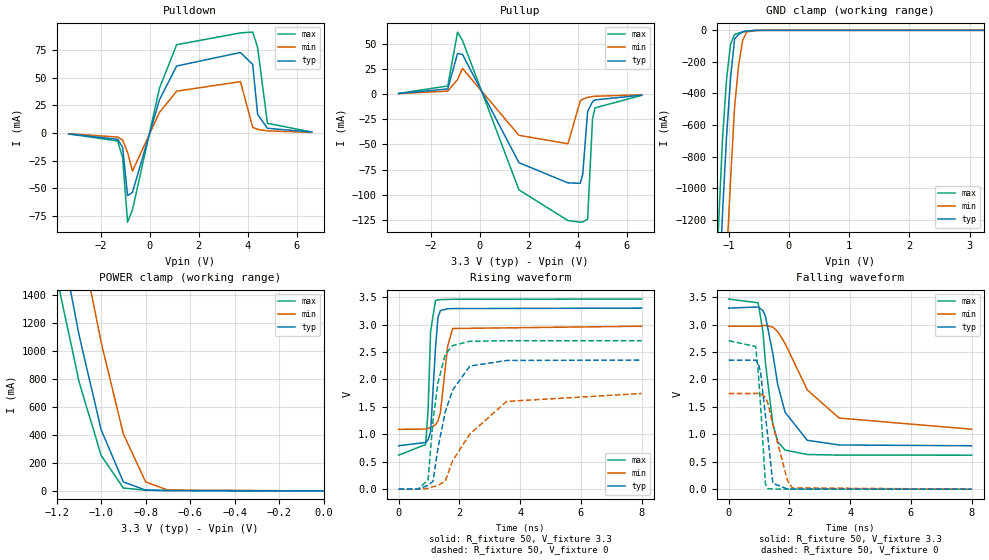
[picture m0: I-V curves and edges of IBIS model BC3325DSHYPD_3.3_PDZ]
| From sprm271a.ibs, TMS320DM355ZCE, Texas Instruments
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|   Model Cell BC3325DSHYPD_3.3_PDZ
[Model]   BC3325DSHYPD_3.3_PDZ
Model_type   I/O
Polarity   Non-Inverting
Enable   Active-Low
Vinl =  1.5
Vinh =  1.8
Cref =  15.0000pF
Rref =  100.0000M
Vref =  0V
Vmeas =  1.65
C_comp   0.972592p   0.9599789p   0.9808023p
[Model Spec]
Vinl   1.5   1.335   1.5825
Vinh   1.8   1.635   1.8825
[Temperature Range]   25   125   -40
[Voltage Range]   3.3   2.97   3.465
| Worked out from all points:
|   slope of the pulldown table from 0 to 0.495 V, typ, clamps not added: 13.9 ohm
|   slope of the pullup table from 0 to 0.495 V, typ, clamps not added: 18.5 ohm
|   GND clamp passes 1 mA (typ) near -0.58 V on its own axis
|   POWER clamp passes 1 mA (typ) near -0.55 V on its own axis
|   rising waveform, R_fixture 50, V_fixture 3.3: 20-80 % time 158ps typ, 222ps min, 118ps max; typ from 0.791 V to 3.3 V
|   rising waveform, R_fixture 50, V_fixture 0: 20-80 % time 596ps typ, 1.31ns min, 352ps max; typ from 0 V to 2.35 V
|   falling waveform, R_fixture 50, V_fixture 3.3: 20-80 % time 565ps typ, 1.23ns min, 332ps max; typ from 3.3 V to 0.791 V
|   falling waveform, R_fixture 50, V_fixture 0: 20-80 % time 265ps typ, 467ps min, 185ps max; typ from 2.35 V to 0 V
[POWER_clamp]
|   voltage   I(typ)   I(min)   I(max)
-3.3V     22.26A     22.98A     21.87A
-1.2V     1.951A     2.729A     1.539A
-1.167V   1.675A     2.441A     1.289A
-1.133V   1.4A       2.153A     1.039A
-1.1V     1.125A     1.865A     788.5mA
-1.067V   896.1mA    1.599A     610.5mA
-1.033V   667.5mA    1.332A     432.6mA
-1V       438.8mA    1.066A     254.7mA
-900mV    64.45mA    408.3mA    20.71mA
-800mV    5.784mA    64.77mA    5.201mA
-700mV    2.596mA    5.81mA     3.131mA
-11.55fV  459.8pA    9.235nA    231.7pA
[Pulldown]
|   voltage   I(typ)   I(min)   I(max)
-3.3V     -808.1uA   -658.5uA   -838.6uA
-1.3V     -5.711mA   -3.626mA   -7.219mA
-1.1V     -12.9mA    -6.318mA   -22.43mA
-900mV    -56.46mA   -17.38mA   -80.42mA
-700mV    -53.51mA   -34.37mA   -69.3mA
400mV     30.01mA    18.55mA    40.42mA
1.1V      60.43mA    37.7mA     79.59mA
3.7V      72.61mA    46.35mA    90.3mA
4.2V      61.81mA    5.119mA    91.01mA
4.4V      16.79mA    3.291mA    77.1mA
4.8V      4.263mA    1.885mA    8.734mA
6.6V      871.4uA    628.5uA    963.3uA
[Pullup]
|   voltage   I(typ)   I(min)   I(max)
-3.3V     659.6uA    522.1uA    739.6uA
-1.3V     5.125mA    2.966mA    8.081mA
-900mV    40.49mA    14.5mA     61.66mA
-700mV    39.49mA    25.52mA    53.37mA
1.6V      -68.17mA   -40.92mA   -95.13mA
3.6V      -88.21mA   -49.34mA   -125.7mA
4.1V      -88.68mA   -6.718mA   -127.3mA
4.2V      -79.89mA   -4.993mA   -127mA
4.4V      -17.25mA   -3.255mA   -124.4mA
4.6V      -7.503mA   -2.398mA   -24.77mA
4.7V      -5.775mA   -2.116mA   -13.67mA
6.6V      -1.03mA    -644.3uA   -1.277mA
[GND_clamp]
|   voltage   I(typ)   I(min)   I(max)
-3.3V     -22.38A    -23.15A    -21.96A
-1.167V   -1.724A    -2.574A    -1.236A
-1.1V     -1.154A    -1.991A    -682.8mA
-1.033V   -667.2mA   -1.446A    -306.2mA
-966.7mV  -300.6mA   -943.8mA   -87.41mA
-900mV    -54.63mA   -483.6mA   -26.4mA
-833.3mV  -26.33mA   -221.3mA   -17.61mA
-766.7mV  -9.637mA   -63.67mA   -10.28mA
-700mV    -4.559mA   -10.62mA   -4.393mA
-566.7mV  -684.4uA   -1.479mA   -425uA
-433.3mV  -37.24uA   -148.7uA   -12.97uA
3.233V    -358.1pA   12.24uA    151.9pA
[Ramp]
| variable   typ   min   max
dV/dt_f   1.518986/0.5662057n   1.136875/1.234065n   1.72203/0.3324217n
dV/dt_r   1.411442/0.5978231n   1.046603/1.31172n   1.623751/0.3450001n
R_load = 50
[Rising Waveform]
R_fixture = 50
V_fixture = 3.3
V_fixture_min = 2.97
V_fixture_max = 3.465
| time   V(typ)   V(min)   V(max)
|   time   V(typ)   V(min)   V(max)
0s        790.9mV    1.09V      619.8mV
888.9ps   850.5mV    1.095V     812.7mV
969.7ps   902.2mV    1.106V     1.458V
1.051ns   1.04V      1.124V     2.875V
1.212ns   2.567V     1.174V     3.438V
1.293ns   3.132V     1.242V     3.45V
1.374ns   3.256V     1.397V     3.454V
1.616ns   3.288V     2.613V     3.459V
1.778ns   3.292V     2.928V     3.461V
8ns       3.3V       2.97V      3.465V
[Rising Waveform]
R_fixture = 50
V_fixture = 0
V_fixture_min = 0
V_fixture_max = 0
| time   V(typ)   V(min)   V(max)
|   time   V(typ)   V(min)   V(max)
0s        34.16nV    295.6nV    3.065nV
646.5ps   -563.6uV   -213.6uV   2.59mV
969.7ps   70.49mV    13.11mV    168.8mV
1.131ns   142.8mV    43.34mV    1.262V
1.293ns   746.6mV    65.7mV     1.937V
1.535ns   1.413V     149.8mV    2.456V
1.778ns   1.805V     519.9mV    2.617V
2.343ns   2.244V     1.003V     2.695V
3.556ns   2.346V     1.599V     2.706V
8ns       2.352V     1.744V     2.706V
[Falling Waveform]
R_fixture = 50
V_fixture = 3.3
V_fixture_min = 2.97
V_fixture_max = 3.465
| time   V(typ)   V(min)   V(max)
|   time   V(typ)   V(min)   V(max)
0s        3.3V       2.97V      3.465V
969.7ps   3.321V     2.97V      3.397V
1.131ns   3.252V     2.98V      2.856V
1.212ns   3.149V     2.986V     2.294V
1.455ns   2.467V     2.954V     1.187V
1.616ns   1.904V     2.872V     863.2mV
1.859ns   1.401V     2.655V     712.6mV
2.586ns   890.9mV    1.811V     631.8mV
3.636ns   805.7mV    1.296V     620.6mV
8ns       790.9mV    1.093V     619.8mV
[Falling Waveform]
R_fixture = 50
V_fixture = 0
V_fixture_min = 0
V_fixture_max = 0
| time   V(typ)   V(min)   V(max)
|   time   V(typ)   V(min)   V(max)
0s        2.352V     1.744V     2.706V
888.9ps   2.35V      1.744V     2.6V
969.7ps   2.297V     1.747V     2.161V
1.051ns   2.13V      1.745V     1.526V
1.212ns   1.332V     1.668V     91.88mV
1.293ns   934.1mV    1.567V     9.454mV
1.455ns   107.7mV    1.176V     3.012mV
1.939ns   2.2mV      151.1mV    864.6uV
2.101ns   1.638mV    23.13mV    585.3uV
8ns       326.2nV    9.667uV    152.3nV
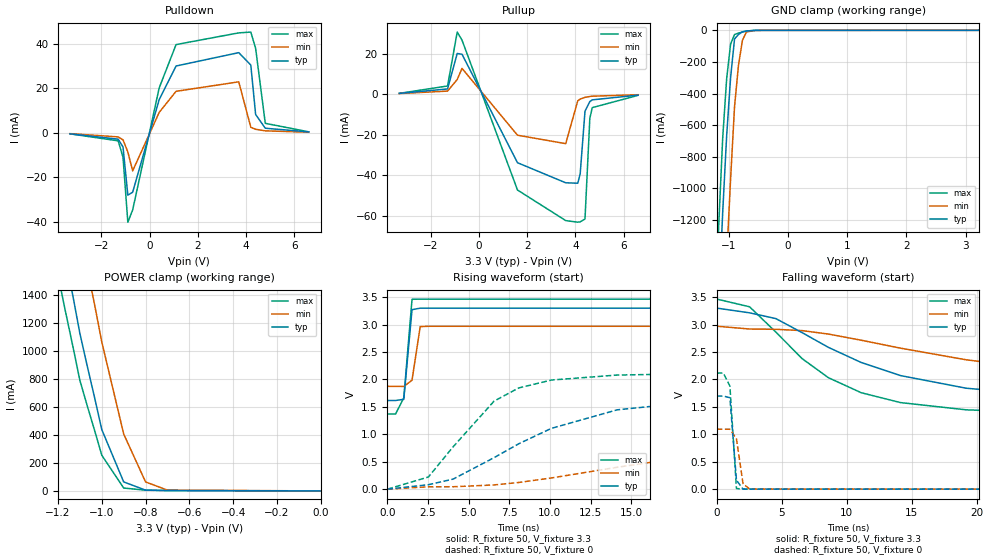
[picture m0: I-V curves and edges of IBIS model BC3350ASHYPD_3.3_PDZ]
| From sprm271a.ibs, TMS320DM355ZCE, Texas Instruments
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|   Model Cell BC3350ASHYPD_3.3_PDZ
[Model]   BC3350ASHYPD_3.3_PDZ
Model_type   I/O
Polarity   Non-Inverting
Enable   Active-Low
Vinl =  1.5
Vinh =  1.8
Cref =  15.0000pF
Rref =  100.0000M
Vref =  0V
Vmeas =  1.65
C_comp   0.972592p   0.9599789p   0.9808023p
[Model Spec]
Vinl   1.5   1.335   1.5825
Vinh   1.8   1.635   1.8825
[Temperature Range]   25   125   -40
[Voltage Range]   3.3   2.97   3.465
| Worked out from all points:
|   slope of the pulldown table from 0 to 0.495 V, typ, clamps not added: 27.9 ohm
|   slope of the pullup table from 0 to 0.495 V, typ, clamps not added: 37.2 ohm
|   GND clamp passes 1 mA (typ) near -0.58 V on its own axis
|   POWER clamp passes 1 mA (typ) near -0.55 V on its own axis
|   rising waveform, R_fixture 50, V_fixture 3.3: 20-80 % time 312ps typ, 340ps min, 354ps max; typ from 1.62 V to 3.3 V
|   rising waveform, R_fixture 50, V_fixture 0: 20-80 % time 7.57ns typ, 16.6ns min, 3.86ns max; typ from 0 V to 1.7 V
|   falling waveform, R_fixture 50, V_fixture 3.3: 20-80 % time 10.4ns typ, 17.4ns min, 6.9ns max; typ from 3.3 V to 1.62 V
|   falling waveform, R_fixture 50, V_fixture 0: 20-80 % time 342ps typ, 406ps min, 343ps max; typ from 1.7 V to 0 V
[POWER_clamp]
|   voltage   I(typ)   I(min)   I(max)
-3.3V     22.26A     22.97A     21.87A
-1.2V     1.948A     2.725A     1.537A
-1.167V   1.673A     2.438A     1.287A
-1.133V   1.398A     2.15A      1.037A
-1.1V     1.122A     1.862A     787.4mA
-1.067V   894.1mA    1.595A     609.8mA
-1.033V   665.8mA    1.329A     432.1mA
-1V       437.5mA    1.062A     254.5mA
-900mV    64.22mA    406.1mA    20.68mA
-800mV    5.761mA    64.16mA    5.182mA
-700mV    2.585mA    5.758mA    3.119mA
-11.55fV  470.2pA    9.255nA    242.2pA
[Pulldown]
|   voltage   I(typ)   I(min)   I(max)
-3.3V     -400.6uA   -325.7uA   -416.4uA
-1.3V     -2.82mA    -1.791mA   -3.561mA
-1.1V     -6.344mA   -3.117mA   -10.94mA
-900mV    -27.92mA   -8.556mA   -40.06mA
-700mV    -26.62mA   -17.03mA   -34.57mA
400mV     14.94mA    9.202mA    20.18mA
1.1V      30.02mA    18.67mA    39.63mA
3.7V      36.02mA    22.92mA    44.89mA
4.2V      30.44mA    2.528mA    45.24mA
4.4V      8.262mA    1.627mA    37.91mA
4.8V      2.109mA    932uA      4.311mA
6.6V      432uA      310.9uA    478.4uA
[Pullup]
|   voltage   I(typ)   I(min)   I(max)
-3.3V     327.2uA    258.8uA    367uA
-1.3V     2.537mA    1.47mA     3.99mA
-900mV    20.03mA    7.176mA    30.58mA
-700mV    19.64mA    12.67mA    26.58mA
1.6V      -33.86mA   -20.29mA   -47.32mA
3.6V      -43.76mA   -24.45mA   -62.41mA
4.1V      -43.98mA   -3.317mA   -63.2mA
4.2V      -39.34mA   -2.467mA   -63.03mA
4.4V      -8.449mA   -1.61mA    -61.61mA
4.6V      -3.699mA   -1.187mA   -12mA
4.7V      -2.851mA   -1.047mA   -6.689mA
6.6V      -510.2uA   -319.1uA   -633uA
[GND_clamp]
|   voltage   I(typ)   I(min)   I(max)
-3.3V     -22.38A    -23.14A    -21.96A
-1.167V   -1.723A    -2.572A    -1.235A
-1.1V     -1.153A    -1.989A    -682mA
-1.033V   -666.2mA   -1.445A    -305.8mA
-966.7mV  -300mA     -942.5mA   -87.23mA
-900mV    -54.47mA   -482.5mA   -26.4mA
-833.3mV  -26.27mA   -220.7mA   -17.62mA
-766.7mV  -9.637mA   -63.42mA   -10.29mA
-700mV    -4.562mA   -10.59mA   -4.398mA
-566.7mV  -685.4uA   -1.478mA   -425.9uA
-433.3mV  -37.31uA   -148.8uA   -13uA
3.233V    -344.9pA   12.19uA    161.3pA
[Ramp]
| variable   typ   min   max
dV/dt_f   1.008831/10.44764n   0.6335448/17.37763n   1.257793/6.885327n
dV/dt_r   1.018225/7.564796n   0.6378128/16.63551n   1.269638/3.850415n
R_load = 50
[Rising Waveform]
R_fixture = 50
V_fixture = 3.3
V_fixture_min = 2.97
V_fixture_max = 3.465
| time   V(typ)   V(min)   V(max)
|   time   V(typ)   V(min)   V(max)
0s        1.616V     1.874V     1.37V
505.1ps   1.616V     1.874V     1.37V
1.01ns    1.638V     1.872V     1.667V
1.515ns   3.272V     1.986V     3.461V
2.02ns    3.299V     2.963V     3.463V
2.525ns   3.299V     2.969V     3.463V
50ns      3.3V       2.97V      3.465V
[Rising Waveform]
R_fixture = 50
V_fixture = 0
V_fixture_min = 0
V_fixture_max = 0
| time   V(typ)   V(min)   V(max)
|   time   V(typ)   V(min)   V(max)
0s        57.97nV    467.1nV    5.476nV
2.525ns   81.21mV    43.43mV    222mV
4.04ns    182.8mV    44.02mV    770.6mV
6.566ns   574.7mV    77.2mV     1.605V
8.081ns   827.4mV    122mV      1.845V
10.1ns    1.109V     204.6mV    1.989V
14.14ns   1.446V     399.1mV    2.08V
19.7ns    1.613V     640mV      2.108V
32.32ns   1.687V     944.8mV    2.115V
50ns      1.696V     1.063V     2.116V
[Falling Waveform]
R_fixture = 50
V_fixture = 3.3
V_fixture_min = 2.97
V_fixture_max = 3.465
| time   V(typ)   V(min)   V(max)
|   time   V(typ)   V(min)   V(max)
0s        3.3V       2.97V      3.465V
2.525ns   3.214V     2.919V     3.324V
4.545ns   3.109V     2.914V     2.863V
6.566ns   2.853V     2.89V      2.379V
8.586ns   2.585V     2.827V     2.032V
11.11ns   2.309V     2.715V     1.758V
14.14ns   2.07V      2.57V      1.578V
19.19ns   1.84V      2.358V     1.446V
25.76ns   1.707V     2.165V     1.391V
50ns      1.62V      1.915V     1.37V
[Falling Waveform]
R_fixture = 50
V_fixture = 0
V_fixture_min = 0
V_fixture_max = 0
| time   V(typ)   V(min)   V(max)
|   time   V(typ)   V(min)   V(max)
0s        1.697V     1.093V     2.116V
505.1ps   1.697V     1.093V     2.116V
1.01ns    1.667V     1.093V     1.88V
1.515ns   163.3mV    916.3mV    11.9mV
2.02ns    1.659mV    100.4mV    1.106mV
2.525ns   697.1uV    2.543mV    907.9uV
50ns      923.8nV    11.67uV    68.56nV
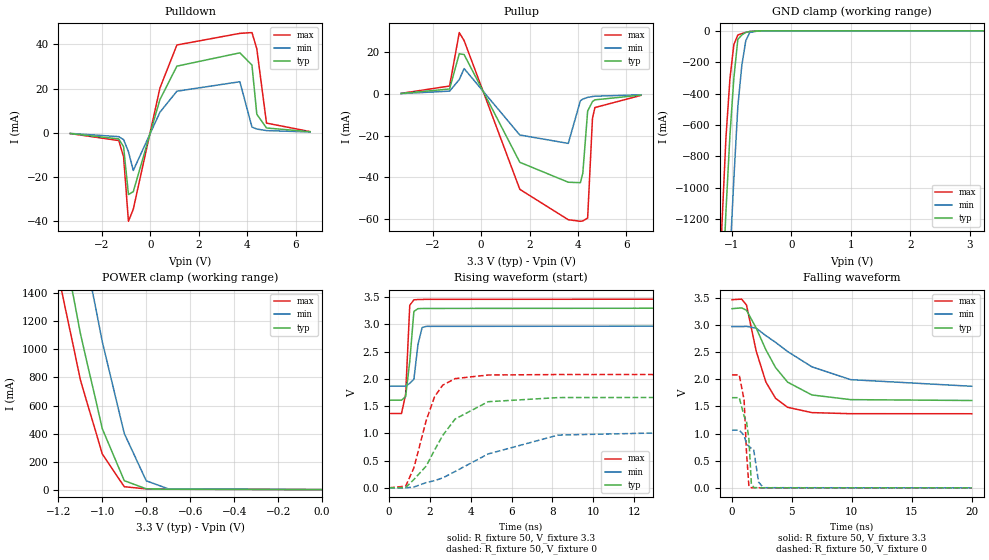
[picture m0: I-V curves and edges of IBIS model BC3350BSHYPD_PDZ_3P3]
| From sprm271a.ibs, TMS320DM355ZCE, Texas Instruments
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|   Model Cell BC3350BSHYPD_PDZ_3P3
[Model]   BC3350BSHYPD_PDZ_3P3
Model_type   I/O
Polarity   Non-Inverting
Enable   Active-Low
Vinl =  0.8V
Vinh =  2V
Cref =  15.0000pF
Rref =  100.0000M
Vref =  0V
Vmeas =  1.65
C_comp   0.972592p   0.9599789p   0.9808023p
[Model Spec]
Vinl   0.8V   0.8V   0.8V
Vinh   2V   2V   2V
[Temperature Range]   25   125   -40
[Voltage Range]   3.3   2.97   3.465
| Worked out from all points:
|   slope of the pulldown table from 0 to 0.495 V, typ, clamps not added: 27.8 ohm
|   slope of the pullup table from 0 to 0.495 V, typ, clamps not added: 38.5 ohm
|   GND clamp passes 1 mA (typ) near -0.58 V on its own axis
|   POWER clamp passes 1 mA (typ) near -0.55 V on its own axis
|   rising waveform, R_fixture 50, V_fixture 3.3: 20-80 % time 258ps typ, 247ps min, 156ps max; typ from 1.61 V to 3.3 V
|   rising waveform, R_fixture 50, V_fixture 0: 20-80 % time 1.71ns typ, 3.78ns min, 963ps max; typ from 0 V to 1.66 V
|   falling waveform, R_fixture 50, V_fixture 3.3: 20-80 % time 2.66ns typ, 4.98ns min, 1.72ns max; typ from 3.3 V to 1.61 V
|   falling waveform, R_fixture 50, V_fixture 0: 20-80 % time 548ps typ, 1.01ns min, 326ps max; typ from 1.66 V to 0 V
[POWER_clamp]
|   voltage   I(typ)   I(min)   I(max)
-3.3V     22.25A     22.96A     21.86A
-1.2V     1.942A     2.716A     1.533A
-1.167V   1.667A     2.429A     1.284A
-1.133V   1.392A     2.141A     1.034A
-1.1V     1.117A     1.853A     785.1mA
-1.067V   889.6mA    1.587A     608.1mA
-1.033V   662.1mA    1.321A     431mA
-1V       434.5mA    1.055A     254mA
-900mV    63.65mA    401mA      20.55mA
-800mV    5.679mA    62.79mA    5.094mA
-700mV    2.541mA    5.63mA     3.065mA
-11.55fV  463.3pA    9.244nA    235.2pA
[Pulldown]
|   voltage   I(typ)   I(min)   I(max)
-3.3V     -402.5uA   -328uA     -417.8uA
-1.3V     -2.834mA   -1.803mA   -3.572mA
-1.1V     -6.374mA   -3.139mA   -10.97mA
-900mV    -28.05mA   -8.614mA   -40.19mA
-700mV    -26.75mA   -17.15mA   -34.68mA
400mV     15mA       9.262mA    20.24mA
1.1V      30.16mA    18.8mA     39.75mA
3.7V      36.2mA     23.1mA     45.03mA
4.2V      30.64mA    2.555mA    45.39mA
4.4V      8.36mA     1.642mA    38.05mA
4.8V      2.125mA    940.1uA    4.346mA
6.6V      434.4uA    313.2uA    480.2uA
[Pullup]
|   voltage   I(typ)   I(min)   I(max)
-3.3V     316.4uA    250.6uA    354.6uA
-1.3V     2.461mA    1.426mA    3.871mA
-900mV    19.37mA    6.99mA     29.52mA
-700mV    18.97mA    12.25mA    25.66mA
1.6V      -32.71mA   -19.62mA   -45.68mA
3.6V      -42.27mA   -23.64mA   -60.25mA
4.1V      -42.48mA   -3.206mA   -61.01mA
4.2V      -37.99mA   -2.385mA   -60.84mA
4.4V      -8.156mA   -1.556mA   -59.46mA
4.6V      -3.571mA   -1.147mA   -11.57mA
4.7V      -2.753mA   -1.012mA   -6.453mA
6.6V      -492.8uA   -308.5uA   -611uA
[GND_clamp]
|   voltage   I(typ)   I(min)   I(max)
-3.3V     -22.38A    -23.14A    -21.96A
-1.167V   -1.723A    -2.572A    -1.235A
-1.1V     -1.153A    -1.989A    -682.1mA
-1.033V   -666.4mA   -1.445A    -305.8mA
-966.7mV  -300.1mA   -942.6mA   -87.25mA
-900mV    -54.49mA   -482.6mA   -26.4mA
-833.3mV  -26.28mA   -220.8mA   -17.62mA
-766.7mV  -9.638mA   -63.45mA   -10.28mA
-700mV    -4.561mA   -10.59mA   -4.396mA
-566.7mV  -684.9uA   -1.478mA   -425.4uA
-433.3mV  -37.27uA   -148.8uA   -12.98uA
3.233V    -338pA     11.98uA    156.1pA
[Ramp]
| variable   typ   min   max
dV/dt_f   1.025503/2.677482n   0.6681133/5.013011n   1.272432/1.721254n
dV/dt_r  0.9974518/1.705582n   0.6379474/3.781955n   1.248806/0.9531159n
R_load = 50
[Rising Waveform]
R_fixture = 50
V_fixture = 3.3
V_fixture_min = 2.97
V_fixture_max = 3.465
| time   V(typ)   V(min)   V(max)
|   time   V(typ)   V(min)   V(max)
0s        1.609V     1.866V     1.365V
606.1ps   1.609V     1.866V     1.365V
808.1ps   1.676V     1.868V     1.717V
1.01ns    2.322V     1.919V     3.352V
1.212ns   3.24V      1.992V     3.452V
1.414ns   3.29V      2.635V     3.458V
1.616ns   3.293V     2.943V     3.459V
1.818ns   3.294V     2.965V     3.461V
20ns      3.3V       2.97V      3.465V
[Rising Waveform]
R_fixture = 50
V_fixture = 0
V_fixture_min = 0
V_fixture_max = 0
| time   V(typ)   V(min)   V(max)
|   time   V(typ)   V(min)   V(max)
0s        56.76nV    457.6nV    5.325nV
808.1ps   6.337mV    -800.1uV   31.09mV
1.212ns   152.4mV    14.44mV    365.8mV
1.818ns   400.7mV    96.07mV    1.238V
2.222ns   690.6mV    131mV      1.67V
2.626ns   962.2mV    182mV      1.886V
3.232ns   1.263V     299.8mV    2.005V
4.848ns   1.581V     621.6mV    2.072V
8.283ns   1.657V     968.7mV    2.08V
20ns      1.661V     1.062V     2.08V
[Falling Waveform]
R_fixture = 50
V_fixture = 3.3
V_fixture_min = 2.97
V_fixture_max = 3.465
| time   V(typ)   V(min)   V(max)
|   time   V(typ)   V(min)   V(max)
0s        3.3V       2.97V      3.465V
808.1ps   3.315V     2.969V     3.476V
1.212ns   3.27V      2.974V     3.367V
2.02ns    2.943V     2.941V     2.519V
2.828ns   2.543V     2.803V     1.949V
3.636ns   2.215V     2.68V      1.649V
4.646ns   1.946V     2.51V      1.483V
6.667ns   1.711V     2.229V     1.386V
9.899ns   1.625V     1.993V     1.366V
20ns      1.609V     1.871V     1.365V
[Falling Waveform]
R_fixture = 50
V_fixture = 0
V_fixture_min = 0
V_fixture_max = 0
| time   V(typ)   V(min)   V(max)
|   time   V(typ)   V(min)   V(max)
0s        1.661V     1.063V     2.08V
606.1ps   1.661V     1.063V     2.08V
1.01ns    1.322V     965.1mV    1.619V
1.212ns   1.222V     809.8mV    653.5mV
1.414ns   890.8mV    764.4mV    20.4mV
1.616ns   79.36mV    725.9mV    3.223mV
1.818ns   6.391mV    692.6mV    2.055mV
2.222ns   2.062mV    106.3mV    1.115mV
2.626ns   1.321mV    2.981mV    720.8uV
20ns      222.3nV    5.533uV    96.52nV
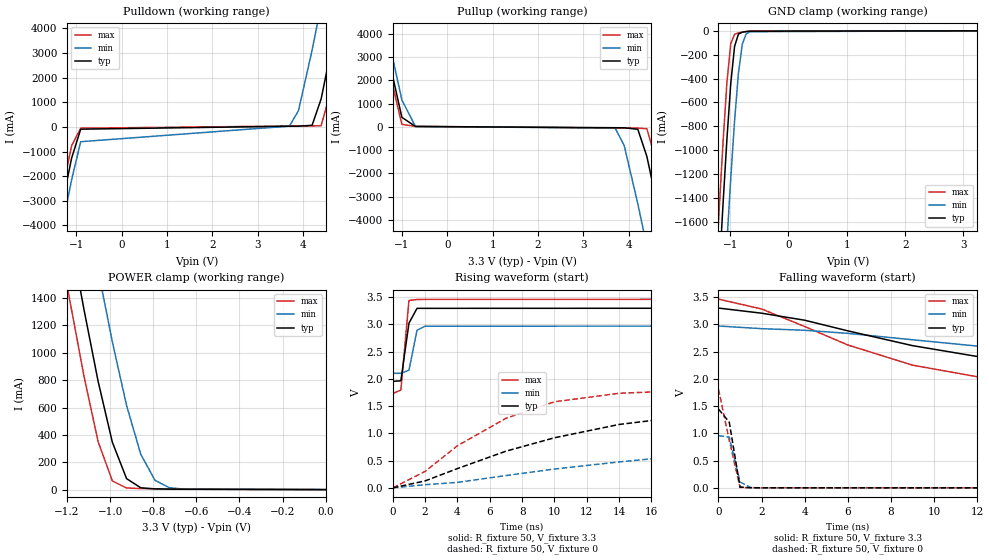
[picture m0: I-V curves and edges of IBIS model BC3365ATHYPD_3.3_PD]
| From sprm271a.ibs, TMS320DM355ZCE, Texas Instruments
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|   Model Cell BC3365ATHYPD_3.3_PD
[Model]   BC3365ATHYPD_3.3_PD
Model_type   I/O
Polarity   Non-Inverting
Enable   Active-Low
Vinl =  1.5
Vinh =  1.8
Cref =  15.0000pF
Rref =  100.0000M
Vref =  0V
Vmeas =  1.65
C_comp   1.4550p   1.4591p   1.4542p
[Model Spec]
Vinl   1.5   1.335   1.5825
Vinh   1.8   1.635   1.8825
[Temperature Range]   25   125   -40
[Voltage Range]   3.3   2.97   3.465
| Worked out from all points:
|   slope of the pulldown table from 0 to 0.495 V, typ, clamps not added: 39.1 ohm
|   slope of the pullup table from 0 to 0.495 V, typ, clamps not added: 46.8 ohm
|   GND clamp passes 1 mA (typ) near -0.58 V on its own axis
|   POWER clamp passes 1 mA (typ) near -0.51 V on its own axis
|   rising waveform, R_fixture 50, V_fixture 3.3: 20-80 % time 393ps typ, 354ps min, 316ps max; typ from 1.95 V to 3.3 V
|   rising waveform, R_fixture 50, V_fixture 0: 20-80 % time 10.4ns typ, 19.8ns min, 6.26ns max; typ from 0 V to 1.45 V
|   falling waveform, R_fixture 50, V_fixture 3.3: 20-80 % time 11.2ns typ, 17.3ns min, 7.96ns max; typ from 3.3 V to 1.95 V
|   falling waveform, R_fixture 50, V_fixture 0: 20-80 % time 364ps typ, 350ps min, 602ps max; typ from 1.45 V to 0 V
[POWER_clamp]
|   voltage   I(typ)   I(min)   I(max)
-3.3V     22.37A     23.13A     21.95A
-1.254V   2.477A     3.334A     1.977A
-1.188V   1.887A     2.741A     1.389A
-1.122V   1.32A      2.163A     832.6mA
-1.056V   791.8mA    1.605A     350.5mA
-990mV    347mA      1.081A     63.9mA
-924mV    80.43mA    615.6mA    11.94mA
-858mV    13.22mA    257.7mA    7.685mA
-792mV    5.282mA    68.12mA    5.961mA
-726mV    3.65mA     14.09mA    4.501mA
-660mV    2.644mA    4.007mA    3.219mA
-7.994fV  93.69uA    51.63uA    142.3uA
[Pulldown]
|   voltage   I(typ)   I(min)   I(max)
-3.3V     -22.52A    -23.33A    -22.07A
-1.6V     -5.868A    -6.754A    -5.356A
-1.4V     -3.969A    -4.867A    -3.446A
-1.1V     -1.269A    -2.15A     -763.7mA
-900mV    -91.24mA   -600mA     -51.56mA
3.7V      28.56mA    33.03mA    36.77mA
3.9V      30.28mA    660.8mA    37.24mA
4.2V      65.85mA    3.119A     41.8mA
4.4V      1.143A     4.959A     50.74mA
4.8V      4.77A      8.763A     2.725A
5.1V      7.648A     11.66A     5.579A
6.6V      22.37A     26.38A     20.32A
[Pullup]
|   voltage   I(typ)   I(min)   I(max)
-3.3V     22.37A     23.13A     21.95A
-1.6V     5.722A     6.562A     5.242A
-1.5V     4.769A     5.616A     4.283A
-1V       414.4mA    1.161A     109.6mA
-700mV    19.48mA    18.8mA     25.53mA
3.7V      -34.46mA   -48.36mA   -45.95mA
3.9V      -35.9mA    -799.7mA   -46.27mA
4.2V      -101.1mA   -3.302A    -52.55mA
4.4V      -1.271A    -5.148A    -77.8mA
4.8V      -4.914A    -8.957A    -2.837A
5.1V      -7.794A    -11.86A    -5.694A
6.6V      -22.52A    -26.58A    -20.44A
[GND_clamp]
|   voltage   I(typ)   I(min)   I(max)
-3.3V     -22.52A    -23.33A    -22.07A
-1.254V   -2.615A    -3.518A    -2.087A
-1.188V   -2.022A    -2.922A    -1.495A
-1.122V   -1.449A    -2.338A    -932.9mA
-1.056V   -911mA     -1.774A    -435.1mA
-990mV    -443mA     -1.238A    -107.9mA
-924mV    -129.3mA   -751.9mA   -28.68mA
-858mV    -27.66mA   -355.1mA   -17.22mA
-792mV    -11.23mA   -111.8mA   -10.69mA
-726mV    -6.13mA    -26.09mA   -5.641mA
-660mV    -3.007mA   -7.179mA   -2.27mA
3.234V    93.67uA    84.38uA    142.2uA
[Ramp]
| variable   typ   min   max
dV/dt_f   0.8079/11.2706n   0.5199/17.2320n   1.0404/7.9319n
dV/dt_r   0.8672/10.4199n   0.5749/19.8491n   1.0868/6.2716n
R_load = 50
[Rising Waveform]
R_fixture = 50
V_fixture = 3.3
V_fixture_min = 2.97
V_fixture_max = 3.465
|   time   V(typ)   V(min)   V(max)
0s        1.954V     2.102V     1.731V
500ps     1.964V     2.1V       1.794V
1ns       3.021V     2.158V     3.438V
1.5ns     3.293V     2.892V     3.455V
2ns       3.293V     2.966V     3.457V
49.5ns    3.298V     2.969V     3.462V
[Rising Waveform]
R_fixture = 50
V_fixture = 0
V_fixture_min = 0
V_fixture_max = 0
|   time   V(typ)   V(min)   V(max)
0s        0V         0V         0V
2ns       127.7mV    58.3mV     302.3mV
4ns       353.9mV    100.4mV    773mV
7ns       672.7mV    225.8mV    1.276V
10ns      918.7mV    345.5mV    1.579V
14ns      1.163V     475.9mV    1.735V
18ns      1.306V     588.8mV    1.783V
22ns      1.376V     686.5mV    1.801V
39ns      1.441V     903.6mV    1.812V
99ns      1.445V     958mV      1.812V
[Falling Waveform]
R_fixture = 50
V_fixture = 3.3
V_fixture_min = 2.97
V_fixture_max = 3.465
|   time   V(typ)   V(min)   V(max)
0s        3.298V     2.969V     3.462V
2ns       3.204V     2.92V      3.281V
4ns       3.075V     2.891V     2.96V
6ns       2.88V      2.834V     2.621V
9ns       2.609V     2.717V     2.251V
13ns      2.344V     2.562V     1.968V
18ns      2.147V     2.408V     1.816V
26ns      2.013V     2.251V     1.747V
40ns      1.961V     2.14V      1.732V
99ns      1.954V     2.102V     1.731V
[Falling Waveform]
R_fixture = 50
V_fixture = 0
V_fixture_min = 0
V_fixture_max = 0
| time   V(typ)   V(min)   V(max)
0s        1.445V     958.2mV    1.812V
500ps     1.205V     930.5mV    873mV
1ns       14.3mV     109mV      7mV
1.5ns     2.7mV      3.2mV      3mV
2ns       1.6mV      1.4mV      1mV
49.5ns    0V         0V         0V
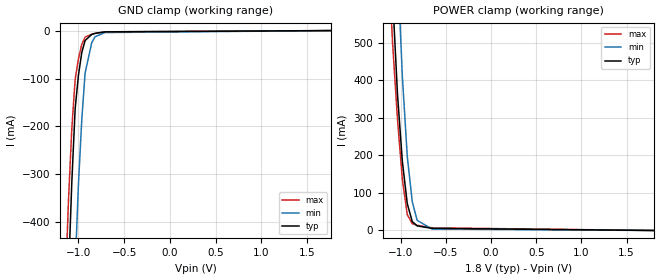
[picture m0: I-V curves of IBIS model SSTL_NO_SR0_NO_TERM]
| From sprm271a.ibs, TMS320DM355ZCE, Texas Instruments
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|   Model Cell SSTL_NO_SR0_NO_TERM
[Model]   SSTL_NO_SR0_NO_TERM
Model_type   Input
Polarity   Non-Inverting
Vinl =  0.80
Vinh =  1.00
C_comp   2.680301p   2.549919p   2.900942p
[Model Spec]
Vinl   0.80   0.71   0.89
Vinh   1.00   0.91   1.09
[Temperature Range]   25   125   -40
[Voltage Range]   1.8   1.62   1.89
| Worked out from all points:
|   GND clamp passes 1 mA (typ) near -0.61 V on its own axis
|   POWER clamp passes 1 mA (typ) near -0.43 V on its own axis
[POWER_clamp]
|   voltage   I(typ)   I(min)   I(max)
-1.8V     6.874A     7.433A     6.58A
-1.127V   860mA      1.357A     680.5mA
-1.109V   744mA      1.219A     591.4mA
-1.091V   627.9mA    1.082A     502.4mA
-1.036V   363.8mA    712.2mA    296.7mA
-1.018V   303.6mA    611.3mA    243mA
-981.8mV  183.1mA    409.5mA    135.6mA
-927.3mV  71.3mA     196.5mA    42.04mA
-872.7mV  23.82mA    77mA       18.25mA
-818.2mV  12.23mA    27.02mA    13.77mA
-654.5mV  5.711mA    3.881mA    6.969mA
1.8V      1.456nA    8.242nA    1.276nA
[GND_clamp]
|   voltage   I(typ)   I(min)   I(max)
-1.8V     -6.675A    -7.171A    -6.432A
-1.145V   -744.7mA   -1.245A    -545.5mA
-1.109V   -512.3mA   -975.8mA   -354.3mA
-1.073V   -318.4mA   -725.5mA   -206.4mA
-1.036V   -163mA     -493.6mA   -101.9mA
-1V       -93.15mA   -320.8mA   -58.47mA
-963.6mV  -45.75mA   -185.9mA   -29.03mA
-927.3mV  -20.78mA   -88.8mA    -13.58mA
-854.5mV  -8.039mA   -25.03mA   -7.576mA
-818.2mV  -5.737mA   -12.83mA   -6.043mA
-709.1mV  -2.669mA   -4.052mA   -2.585mA
1.764V    -1.54nA    1.734uA    1.05nA
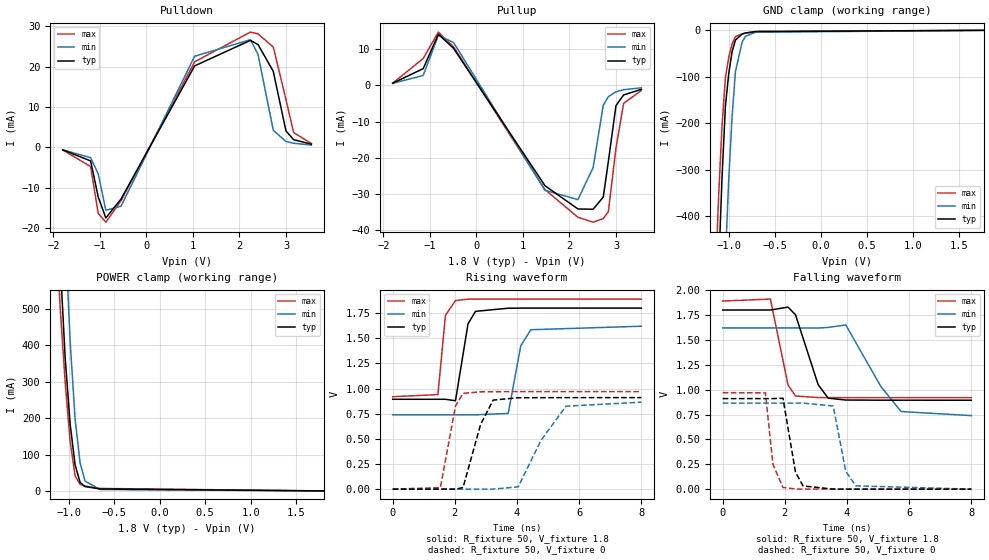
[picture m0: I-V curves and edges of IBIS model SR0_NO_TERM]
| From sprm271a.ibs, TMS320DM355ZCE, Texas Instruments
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|   Model Cell SR0_NO_TERM
[Model]   SR0_NO_TERM
Model_type   I/O
Polarity   Non-Inverting
Enable   Active-Low
Vinl =  0.80
Vinh =  1.00
Cref =  15.0000pF
Rref =  100.0000M
Vref =  0V
Vmeas =  0.9
C_comp   2.680301p   2.549919p   2.900942p
[Model Spec]
Vinl   0.80   0.71   0.89
Vinh   1.00   0.91   1.09
[Temperature Range]   25   125   -40
[Voltage Range]   1.8   1.62   1.89
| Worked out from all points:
|   slope of the pulldown table from 0 to 0.27 V, typ, clamps not added: 43.8 ohm
|   slope of the pullup table from 0 to 0.27 V, typ, clamps not added: 46.4 ohm
|   GND clamp passes 1 mA (typ) near -0.61 V on its own axis
|   POWER clamp passes 1 mA (typ) near -0.44 V on its own axis
|   rising waveform, R_fixture 50, V_fixture 1.8: 20-80 % time 209ps typ, 273ps min, 178ps max; typ from 0.894 V to 1.8 V
|   rising waveform, R_fixture 50, V_fixture 0: 20-80 % time 493ps typ, 910ps min, 335ps max; typ from 0 V to 0.91 V
|   falling waveform, R_fixture 50, V_fixture 1.8: 20-80 % time 554ps typ, 974ps min, 351ps max; typ from 1.8 V to 0.894 V
|   falling waveform, R_fixture 50, V_fixture 0: 20-80 % time 219ps typ, 294ps min, 183ps max; typ from 0.91 V to 0 V
[POWER_clamp]
|   voltage   I(typ)   I(min)   I(max)
-1.8V     6.874A     7.433A     6.58A
-1.127V   860mA      1.357A     680.3mA
-1.109V   743.9mA    1.219A     591.2mA
-1.091V   627.9mA    1.082A     502.1mA
-1.036V   363.7mA    712.2mA    296.4mA
-1.018V   303.5mA    611.3mA    242.6mA
-981.8mV  183mA      409.5mA    135.2mA
-927.3mV  71.09mA    196.5mA    41.52mA
-872.7mV  23.54mA    77mA       17.73mA
-818.2mV  11.93mA    27.02mA    13.33mA
-654.5mV  5.543mA    3.881mA    6.744mA
1.8V      1.289nA    8.242nA    1.276nA
[Pulldown]
|   voltage   I(typ)   I(min)   I(max)
-1.8V     -630.9uA   -647.2uA   -654.9uA
-1.2V     -3.389mA   -2.58mA    -4.785mA
-1.036V   -12.36mA   -6.638mA   -16.44mA
-872.7mV  -17.56mA   -15.65mA   -18.61mA
-545.5mV  -12.84mA   -14.64mA   -13.28mA
1.036V    20.21mA    22.61mA    21.23mA
2.236V    26.56mA    26.72mA    28.61mA
2.4V      25.5mA     23.06mA    28.16mA
2.727V    18.86mA    4.214mA    24.91mA
3V        4.055mA    1.456mA    11.86mA
3.164V    1.895mA    997.4uA    3.665mA
3.545V    766.5uA    554.8uA    930uA
[Pullup]
|   voltage   I(typ)   I(min)   I(max)
-1.8V     599.9uA    567.3uA    597.4uA
-1.145V   4.624mA    2.745mA    7.43mA
-818.2mV  14.15mA    13.83mA    14.74mA
-490.9mV  10.23mA    11.84mA    10.64mA
1.473V    -27.76mA   -29.04mA   -28.84mA
2.182V    -34.2mA    -31.6mA    -36.5mA
2.509V    -34.28mA   -22.76mA   -37.86mA
2.727V    -30.91mA   -5.511mA   -36.86mA
2.836V    -21.09mA   -3.124mA   -34.95mA
3V        -5.604mA   -1.78mA    -17.37mA
3.164V    -2.647mA   -1.211mA   -4.992mA
3.545V    -1.105mA   -672.2uA   -1.404mA
[GND_clamp]
|   voltage   I(typ)   I(min)   I(max)
-1.8V     -6.675A    -7.171A    -6.432A
-1.145V   -744.8mA   -1.245A    -545.6mA
-1.109V   -512.4mA   -975.8mA   -354.4mA
-1.073V   -318.5mA   -725.5mA   -206.5mA
-1.036V   -163.2mA   -493.6mA   -102mA
-1V       -93.34mA   -320.8mA   -58.49mA
-963.6mV  -45.91mA   -185.9mA   -29.01mA
-927.3mV  -20.88mA   -88.8mA    -13.53mA
-854.5mV  -8.057mA   -25.03mA   -7.542mA
-818.2mV  -5.731mA   -12.83mA   -6.017mA
-709.1mV  -2.662mA   -4.052mA   -2.579mA
1.764V    -1.607nA   1.734uA    1.056nA
[Ramp]
| variable   typ   min   max
dV/dt_f  0.7534137/0.7983648n  0.7370505/1.407434n   0.803032/0.5146069n
dV/dt_r  0.7336134/0.6958663n  0.6983713/1.266042n   0.7804824/0.4689114n
R_load = 50
[Rising Waveform]
R_fixture = 50
V_fixture = 1.8
V_fixture_min = 1.62
V_fixture_max = 1.89
| time   V(typ)   V(min)   V(max)
|   time   V(typ)   V(min)   V(max)
0s        893.6mV    738.9mV    919.1mV
1.455ns   893.6mV    738.9mV    940.2mV
1.697ns   893.6mV    738.9mV    1.728V
2.02ns    878.9mV    738.9mV    1.875V
2.424ns   1.645V     738.9mV    1.889V
2.667ns   1.768V     738.9mV    1.889V
3.717ns   1.799V     752.7mV    1.89V
4.121ns   1.8V       1.425V     1.89V
4.444ns   1.8V       1.585V     1.89V
8ns       1.8V       1.62V      1.89V
[Rising Waveform]
R_fixture = 50
V_fixture = 0
V_fixture_min = 0
V_fixture_max = 0
| time   V(typ)   V(min)   V(max)
|   time   V(typ)   V(min)   V(max)
0s        185nV      528.9nV    19.26nV
1.535ns   3.32uV     528.9nV    15.18mV
2.02ns    -295uV     300.4nV    826.3mV
2.263ns   15.66mV    631nV      952.2mV
2.828ns   643.6mV    -7.081uV   967.8mV
3.232ns   885.4mV    448uV      968.7mV
4.04ns    908.9mV    23.08mV    969.2mV
4.768ns   909.7mV    483.9mV    969.3mV
5.576ns   909.9mV    824.8mV    969.3mV
8ns       910mV      864.7mV    969.3mV
[Falling Waveform]
R_fixture = 50
V_fixture = 1.8
V_fixture_min = 1.62
V_fixture_max = 1.89
| time   V(typ)   V(min)   V(max)
|   time   V(typ)   V(min)   V(max)
0s        1.8V       1.62V      1.89V
1.535ns   1.8V       1.62V      1.91V
2.101ns   1.829V     1.62V      1.047V
2.343ns   1.752V     1.62V      936.3mV
3.071ns   1.05V      1.619V     920.4mV
3.394ns   914.4mV    1.625V     919.6mV
3.96ns    895.5mV    1.65V      919.3mV
5.091ns   894mV      1.031V     919.1mV
5.737ns   893.8mV    780mV      919.1mV
8ns       893.7mV    739.1mV    919.1mV
[Falling Waveform]
R_fixture = 50
V_fixture = 0
V_fixture_min = 0
V_fixture_max = 0
| time   V(typ)   V(min)   V(max)
|   time   V(typ)   V(min)   V(max)
0s        910mV      864.8mV    969.3mV
1.374ns   910mV      864.8mV    967.9mV
1.616ns   910mV      864.8mV    248.8mV
1.939ns   913.5mV    864.8mV    16.95mV
2.343ns   169mV      864.8mV    1.97mV
2.586ns   32.35mV    864.8mV    1.047mV
3.556ns   887.9uV    835.8mV    156.1uV
3.96ns    425.3uV    179mV      71.01uV
4.283ns   260.5uV    33.42mV    37.48uV
8ns       -37.55nV   41.57uV    -815.9nV
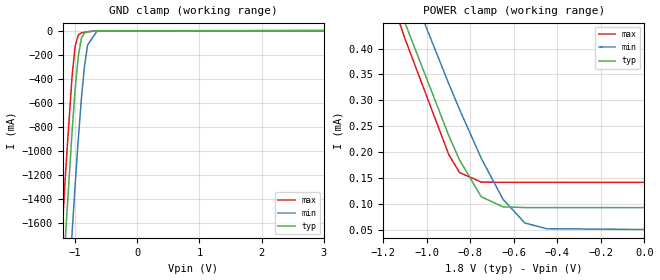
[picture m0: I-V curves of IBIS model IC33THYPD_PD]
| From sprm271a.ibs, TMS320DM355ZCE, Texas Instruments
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|   Model Cell IC33THYPD_PD
[Model]   IC33THYPD_PD
Model_type   Input
Polarity   Non-Inverting
Vinl =  0.513
Vinh =  1.323
|Variable   typ   min   max
C_comp   1.64pF   1.63pF   1.65pF
[Temperature Range]   25   125   -40
[Voltage Range]   1.8   1.71   1.89
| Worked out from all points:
|   GND clamp passes 1 mA (typ) near -0.59 V on its own axis
|   POWER clamp passes 1 mA (typ) near -1.57 V on its own axis
[POWER_clamp]
|   voltage   I(typ)   I(min)   I(max)
-3.3V     3.111mA    3.042mA    3.326mA
-1.25V    621.2uA    705.7uA    605.3uA
-1.2V     563.2uA    651uA      542.1uA
-1.15V    505.7uA    596.6uA    479.6uA
-1.1V     448.8uA    542.6uA    418uA
-900mV    233uA      332.8uA    196.3uA
-850mV    185.5uA    282.8uA    161.2uA
-750mV    114.6uA    188.6uA    142.9uA
-650mV    95.16uA    109.8uA    142.4uA
-550mV    93.82uA    64.24uA    142.4uA
-450mV    93.77uA    53.1uA     142.4uA
0V        93.69uA    51.63uA    142.3uA
[GND_clamp]
|   voltage   I(typ)   I(min)   I(max)
-3.3V     -22.49A    -23.28A    -22.04A
-1.25V    -2.547A    -3.439A    -2.025A
-1.2V     -2.098A    -2.987A    -1.576A
-1.15V    -1.659A    -2.543A    -1.142A
-1.05V    -837.3mA   -1.685A    -376.4mA
-1V       -483mA     -1.28A     -126.8mA
-950mV    -209.8mA   -901.6mA   -35.83mA
-900mV    -63.74mA   -564.5mA   -19.14mA
-850mV    -20.29mA   -293.8mA   -13.54mA
-800mV    -10.15mA   -118.7mA   -9.446mA
-650mV    -2.194mA   -5.142mA   -1.593mA
3.3V      93.69uA    51.72uA    142.2uA
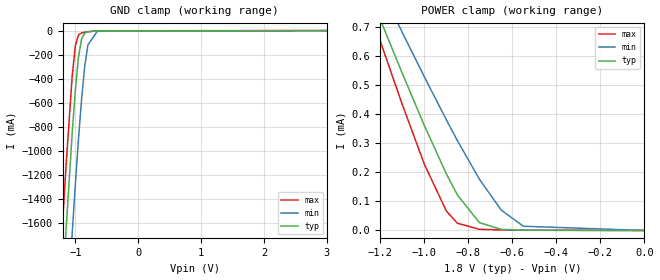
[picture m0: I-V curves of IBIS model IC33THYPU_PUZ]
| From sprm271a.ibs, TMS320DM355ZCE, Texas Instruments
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|   GS50 Cell IC33THYPU
|   Model Cell IC33THYPU_PUZ
[Model]   IC33THYPU_PUZ
Model_type   Input
Polarity   Non-Inverting
Vinl =  0.513
Vinh =  1.323
|Variable   typ   min   max
C_comp   1.003pF   0.997pF   1.007pF
[Temperature Range]   25   125   -40
[Voltage Range]   1.8   1.71   1.89
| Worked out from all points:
|   GND clamp passes 1 mA (typ) near -0.60 V on its own axis
|   POWER clamp passes 1 mA (typ) near -1.34 V on its own axis
[POWER_clamp]
|   voltage   I(typ)   I(min)   I(max)
-3.3V     4.823mA    4.248mA    5.519mA
-1.25V    820.6uA    916uA      764.1uA
-1.2V     726.5uA    837.4uA    652.4uA
-1.15V    633.2uA    759.4uA    542.1uA
-1.1V     541uA      681.9uA    433.8uA
-1V       361.7uA    529.3uA    228.5uA
-900mV    195.4uA    381.2uA    67.34uA
-850mV    122.8uA    309.9uA    25.17uA
-750mV    27.22uA    176.9uA    4.108uA
-650mV    3.537uA    69.93uA    1.986uA
-550mV    972nA      14.6uA     813.4nA
0V        417.9pA    11.12nA    174pA
[GND_clamp]
|   voltage   I(typ)   I(min)   I(max)
-3.3V     -22.5A     -23.28A    -22.04A
-1.25V    -2.564A    -3.439A    -2.025A
-1.2V     -2.114A    -2.987A    -1.576A
-1.15V    -1.675A    -2.543A    -1.142A
-1.05V    -852.9mA   -1.685A    -376.4mA
-1V       -496.8mA   -1.28A     -126.8mA
-950mV    -219.6mA   -901.6mA   -35.74mA
-900mV    -67.85mA   -564.5mA   -19.04mA
-850mV    -21.21mA   -293.8mA   -13.45mA
-800mV    -10.31mA   -118.6mA   -9.356mA
-650mV    -2.192mA   -5.106mA   -1.52mA
3.3V      417.9pA    145.6nA    154.1pA
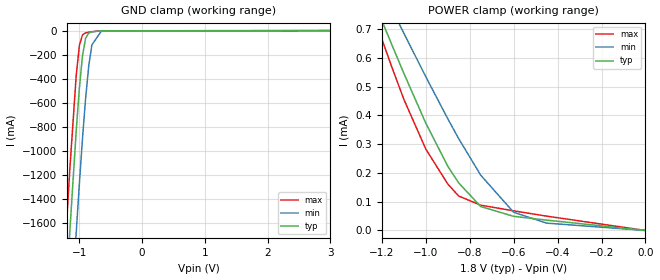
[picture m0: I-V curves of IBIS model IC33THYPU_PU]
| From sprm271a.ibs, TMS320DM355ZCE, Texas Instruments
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|   Model Cell IC33THYPU_PU
[Model]   IC33THYPU_PU
Model_type   Input
Polarity   Non-Inverting
Vinl =  0.513
Vinh =  1.323
|Variable   typ   min   max
C_comp   1.003pF   0.997pF   1.007pF
[Temperature Range]   25   125   -40
[Voltage Range]   1.8   1.71   1.89
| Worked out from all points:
|   GND clamp passes 1 mA (typ) near -0.59 V on its own axis
|   POWER clamp passes 1 mA (typ) near -1.34 V on its own axis
[POWER_clamp]
|   voltage   I(typ)   I(min)   I(max)
-3.3V     4.829mA    4.249mA    5.52mA
-1.25V    823uA      918.9uA    774.5uA
-1.2V     729.5uA    840.6uA    665.1uA
-1.15V    637.3uA    762.9uA    558.5uA
-1.1V     546.5uA    685.9uA    456.3uA
-1V       373.1uA    534.4uA    283uA
-900mV    223.6uA    388.5uA    161.6uA
-850mV    165.2uA    318.9uA    119.6uA
-750mV    83.22uA    192.3uA    88uA
-600mV    49.18uA    63.18uA    68.25uA
-450mV    35.99uA    25.56uA    49.89uA
0V        379pA      11.12nA    172.6pA
[GND_clamp]
|   voltage   I(typ)   I(min)   I(max)
-3.3V     -22.49A    -23.28A    -22.04A
-1.25V    -2.547A    -3.439A    -2.025A
-1.2V     -2.098A    -2.987A    -1.576A
-1.15V    -1.659A    -2.543A    -1.142A
-1.05V    -837.3mA   -1.685A    -376.4mA
-1V       -483mA     -1.28A     -126.9mA
-950mV    -209.8mA   -901.6mA   -35.87mA
-900mV    -63.76mA   -564.5mA   -19.18mA
-850mV    -20.32mA   -293.8mA   -13.6mA
-800mV    -10.19mA   -118.7mA   -9.503mA
-650mV    -2.246mA   -5.169mA   -1.668mA
3.3V      379pA      17.51uA    -16.41uA
